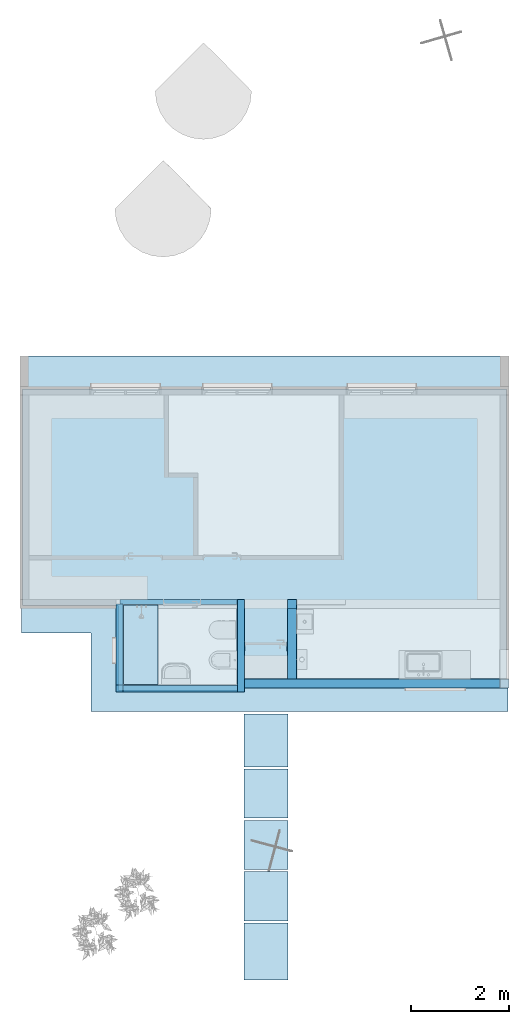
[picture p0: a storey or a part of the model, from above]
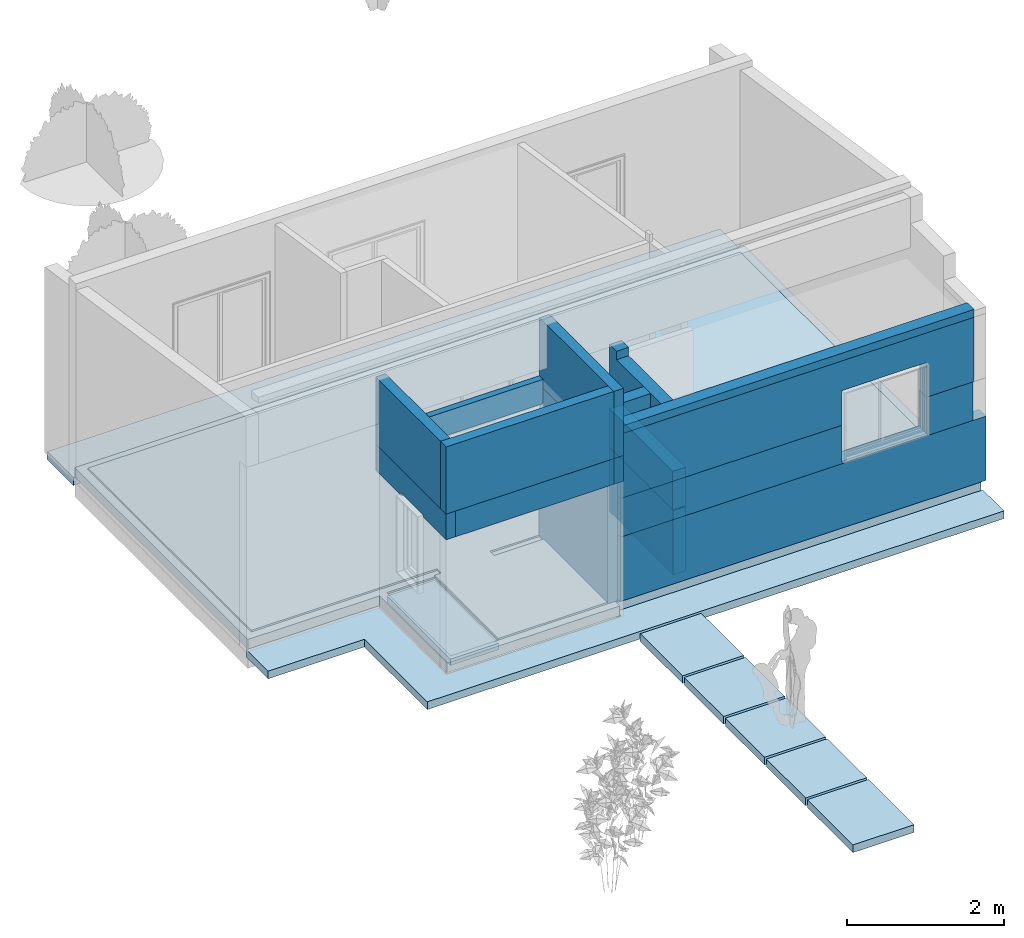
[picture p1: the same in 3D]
Properties of the parts of a building model (IFC2X3)

# File
Description: ViewDefinition [CoordinationView_V2.0]
File name: Project Number
Time: 2021-10-06T08:26:32
Written by: The EXPRESS Data Manager Version 5.02.0100.07 : 28 Aug 2013
Made in: 20200210_1400(x64) - Exporter 20.2.12.1 - Alternate UI 20.2.12.1
Comment: STEP Physical File produced by: The EXPRESS Data Manager Version 5.02.0100.07 : 28 Aug 2013 * Module: EDMstepFileFactory/EDMstandAlone * Creation date: Wed Oct 06 08:26:32 2021 * Host: d-417 * Database: C:\Users\msoler\AppData\Local\Temp\011061c9-1817-4c47-bff8-884cf63e469e\37fb6d74-e1f5-403b-9660-fe2e54388b5f\ifc * Database version: 5507 * Database creation date: Wed Oct 06 08:26:29 2021 * Schema: IFC2X3 * Model: DataRepository.ifc * Model creation date: Wed Oct 06 08:26:30 2021 * Header model: DataRepository.ifc_HeaderModel * Header model creation date: Wed Oct 06 08:26:30 2021 * EDMuser: sdai-user * EDMgroup: sdai-group * License ID and type: 5605 : Permanent license. Expiry date: * EDMstepFileFactory options: 020000

# IfcProject, Project Number
LongName: Project Name; Phase: Project Status

# IfcSite, Surface:604594
RefLatitude: 42, 21, 31, 181945; RefLongitude: -71, -3, -24, -263305; RefElevation: 0 m
Pset_ProductRequirements - Category: Topography

# IfcBuilding
Pset_BuildingCommon - NumberOfStoreys: 2
Pset_ProductRequirements - Category: Project Information

# IfcBuildingStorey: Level:8mm Head (2)
Pset_ProductRequirements - Category: Levels
Name | LongName = Pset_AirSideSystemInformation, Name = Pset_ProductRequirements, Name | Elevation (m)
Nivel 0.0 | Nivel 0.0 | 0
Nivel 1 | Nivel 1 | 2.7

# IfcSpace (6)
In: Nivel 0.0
InteriorOrExteriorSpace: INTERNAL
Pset_ProductRequirements - Category: Rooms
Pset_SpaceCommon - Category: Rooms; FloorCovering: Cerámico; CeilingCovering: placa yeso suspendido
Name | LongName = Pset_AirSideSystemInformation, Name = Pset_ProductRequirements, Name | Reference
1 | Hall distribuidor y paso | Hall distribuidor y paso 1
2 | Estar comedor | Estar comedor 2
4 | Dormitorio 1 | Dormitorio 1 4
5 | Dormitorio 2 | Dormitorio 2 5
6 | Baño | Baño 6 | Pset_SpaceCommon - WallCovering: cerámico
3 | Lavadero | Lavadero 3 | Pset_SpaceCommon - WallCovering: cerámico

# IfcBuildingElementProxy: Barberry - 1.0 Meters (3)
In: Nivel 0.0
Type - Pset_BuildingElementProxyCommon - Reference: Barberry - 1.0 Meters
Type - Pset_ProductRequirements - Category: Planting
Type - Pset_QuantityTakeOff - Reference: Barberry - 1.0 Meters
Pset_BuildingElementProxyCommon - sets with these values: 2
Name (M_RPC Shrub:Barberry - 1.0 Meters:...)
617424
617426
707226

# IfcBuildingElementProxy: Enscape AssetDefinition - Bamboo 5 (2)
In: Nivel 0.0
Type - Pset_BuildingElementProxyCommon - Reference: Enscape AssetDefinition - Bamboo 5
Type - Pset_ProductRequirements - Category: Planting
Type - Pset_QuantityTakeOff - Reference: Enscape AssetDefinition - Bamboo 5
Pset_BuildingElementProxyCommon - sets with these values: 2
Name (Bamboo:Enscape AssetDefinition - Bamboo 5:...)
669530
671551

# IfcBuildingElementProxy: People_01_Multiple_views_persona_01_Vistas_multiples_3530 (2)
In: Nivel 0.0
Type - Material: Sombra escala
Type - Pset_BuildingElementProxyCommon - Reference: People_01_Multiple_views_persona_01_Vistas_multiples_3530
Type - Pset_ProductRequirements - Category: Entourage
Type - Pset_QuantityTakeOff - Reference: People_01_Multiple_views_persona_01_Vistas_multiples_3530
Pset_BuildingElementProxyCommon - sets with these values: 2
Name (People_01_Multiple_views_persona_01_Vistas_multiples_3530:People_01_Multiple_views_persona_01_Vistas_multiples_3530:...)
621565
707233

# IfcBuildingElementProxy: Slab Edge:Slab Edge, Slab Edge:Slab Edge:727210
In: Nivel 0.0
Pset_BuildingElementProxyCommon - Reference: Slab Edge; sets with these values: 2
Pset_ProductRequirements - Category: Slab Edges

# IfcBuildingElementProxy: calentador solar techo inclinado, calentador solar techo inclinado:calentador solar techo inclinado:707159
In: Nivel 1
Type - Material: Aluminio, Acero inoxidable, UHMW, rojo, Laminado, marino
Type - Pset_BuildingElementProxyCommon - Reference: calentador solar techo inclinado
Type - Pset_ManufacturerTypeInformation - Manufacturer: Bicentenario Calentadores solares
Type - Pset_ProductRequirements - Category: Mechanical Equipment
Type - Pset_QuantityTakeOff - Reference: calentador solar techo inclinado
Pset_BuildingElementProxyCommon - sets with these values: 2

# IfcCovering: Compound Ceiling:1282-Aplicado de yeso (4)
Type - PredefinedType: CEILING
Type - Pset_CoveringCommon - Reference: 1282-Aplicado de yeso; TotalThickness: 0.02 m
Type - Pset_ElementShading - Roughness: 0.3048 m
Type - Pset_ProductRequirements - Category: Ceilings
Type - Pset_QuantityTakeOff - Reference: 1282-Aplicado de yeso
Material: Cielorraso aplicado de yeso 0.02 m
Name (Compound Ceiling:1282-Aplicado de yeso:...) | In
452097 | Nivel 1
452149 | Nivel 0.0
707047 | 6
721033 | Nivel 0.0

# IfcDistributionPort (8)
Description: Flow
Name | FlowDirection
Port_707095 | SINK
Port_707095 | SOURCE
Port_707096 | SINK
2 x Port_707096 | SOURCE
Port_707125 | SINK
2 x Port_707159 | SOURCEANDSINK

# IfcDoor: P1, Puerta acceso:P1:725328
In: Nivel 0.0
Type - OperationType: SINGLE_SWING_RIGHT; ParameterTakesPrecedence: no; Sizeable: no; Material: Aluminum, Metal, Paint Finish, White, Matte
Type - Puerta acceso:P1:725328 - PanelOperation: SWINGING
OverallHeight: 2.1 m; OverallWidth: 0.85 m
Pset_DoorCommon - IsExternal: no; Reference: P1
Pset_ProductRequirements - Category: Doors
Pset_QuantityTakeOff - Reference: P1

# IfcDoor: P3 (3)
In: Nivel 0.0
Type - ParameterTakesPrecedence: no; Sizeable: no; Material: Bronce Platil, 0 - BLANCO, Pintura Esmalte Blanco Satinado
OverallHeight: 2.1 m; OverallWidth: 0.78 m
Pset_DoorCommon - IsExternal: no; Reference: P3
Pset_ProductRequirements - Category: Doors
Pset_QuantityTakeOff - Reference: P3
Name (Puerta Interior:P3:...)
707092
707093
707094

# IfcFlowTerminal: Bacha-Ferrum-Qubiq-L12K:Sin Agujero, Bacha-Ferrum-Qubiq-L12K:Sin Agujero:707125
In: 3
Material: Ceramica - Ferrum - Blanco
Pset_DistributionFlowElementCommon - Reference: Sin Agujero; sets with these values: 2
Pset_ManufacturerTypeInformation - Manufacturer: Ferrum
Pset_ProductRequirements - Category: Plumbing Fixtures

# IfcFlowTerminal: Bidet-Ferrum-Veneto-1_y_3_Agujeros:1 Agujero, Bidet-Ferrum-Veneto-1_y_3_Agujeros:1 Agujero:707096
In: 6
Material: Ceramica - Ferrum - Blanco
Pset_DistributionFlowElementCommon - Reference: 1 Agujero; sets with these values: 2
Pset_ManufacturerTypeInformation - Manufacturer: Ferrum
Pset_ProductRequirements - Category: Plumbing Fixtures

# IfcFlowTerminal: Cdo Ducha:Cdo Ducha, Cdo Ducha:Cdo Ducha:707099
In: 6
Material: 0 - BLANCO, Metal - Cromo pulido
Pset_DistributionFlowElementCommon - Reference: Cdo Ducha; sets with these values: 2
Pset_ProductRequirements - Category: Plumbing Fixtures

# IfcFlowTerminal: Inodoro-Ferrum-Veneto-Corto:Inodoro Corto, Inodoro-Ferrum-Veneto-Corto:Inodoro Corto:707095
In: 6
Material: Ceramica - Ferrum - Blanco
Pset_DistributionFlowElementCommon - Reference: Inodoro Corto; sets with these values: 2
Pset_ManufacturerTypeInformation - Manufacturer: Ferrum
Pset_ProductRequirements - Category: Plumbing Fixtures

# IfcFlowTerminal: Inodoro-Ferrum-Veneto-Tapa_y_Asiento:Tapa de Inodoro, Inodoro-Ferrum-Veneto-Tapa_y_Asiento:Tapa de Inodoro:707270
In: 6
Material: Plastico - Ferrum - Urea - Blanco
Pset_DistributionFlowElementCommon - Reference: Tapa de Inodoro; sets with these values: 2
Pset_ManufacturerTypeInformation - Manufacturer: Ferrum
Pset_ProductRequirements - Category: Plumbing Fixtures

# IfcFlowTerminal: Lavatorio:Lavatorio, Lavatorio:Lavatorio:707098
In: 6
Material: Porcelain
Pset_DistributionFlowElementCommon - Reference: Lavatorio; sets with these values: 2
Pset_ProductRequirements - Category: Plumbing Fixtures

# IfcFlowTerminal: M_Sink Kitchen-Single:760 x 535mm, M_Sink Kitchen-Single:760 x 535mm:707124
In: 2
Material: Steel, Polished
Pset_DistributionFlowElementCommon - Reference: 760 x 535mm; sets with these values: 2
Pset_ProductRequirements - Category: Plumbing Fixtures

# IfcFurnishingElement: EH-Esquentador a Gáz, CALEFON:EH-Esquentador a Gáz:707126
In: 3
Type - Material: Glass, EH - Preto, EH - Branco
Pset_ManufacturerTypeInformation - Manufacturer: Vulcano
Pset_ProductRequirements - Category: Casework
Pset_QuantityTakeOff - Reference: EH-Esquentador a Gáz

# IfcFurnishingElement: Mesada 1.45m, M_Counter Top w Sink:Mesada 1.45m:707123
In: 2
Type - Material: Stone
Pset_ProductRequirements - Category: Casework
Pset_QuantityTakeOff - Reference: Mesada 1.45m

# IfcOpeningElement: Opening (21)
Name | In
Basic Wall:Pe-SF-002:706994:1 | Nivel 0.0 | Pset_ElementShading - Roughness: 0.3048 m; Pset_ProductRequirements - Category: Walls; Pset_QuantityTakeOff - Reference: Pe-SF-002; sets with these values: 2
Basic Wall:Pi-SF-050:706999 | Nivel 0.0 | Pset_ElementShading - Roughness: 0.3048 m; Pset_ProductRequirements - Category: Walls; Pset_QuantityTakeOff - Reference: Pi-SF-050; sets with these values: 2
Floor:Platea de fundación:707003:2 | Nivel 0.0 | Pset_ElementShading - Roughness: 0.9144 m; Pset_ProductRequirements - Category: Floors; Pset_OpeningElementCommon - Reference: Platea de fundación; sets with these values: 2
Basic Wall:Pe-SF-001:707091:1 | Nivel 0.0 | Pset_ElementShading - Roughness: 0.3048 m; Pset_ProductRequirements - Category: Walls; Pset_QuantityTakeOff - Reference: Pe-SF-001; sets with these values: 2
Ventana1,20x1.20:V1:817578:1 | Nivel 0.0
M_Counter Top w Sink:Mesada 1.45m:707123:1 | 2 | Pset_ProductRequirements - Category: Casework; Pset_OpeningElementCommon - Reference: Mesada 1.45m; sets with these values: 2
Ventana batiente horizontal V2:V2:805811:1 | Nivel 0.0
2 x Basic Wall:Pe-SF-005:808462 | Nivel 0.0 | Pset_ElementShading - Roughness: 0.3048 m; Pset_ProductRequirements - Category: Walls; Pset_QuantityTakeOff - Reference: Pe-SF-005; sets with these values: 2
2 x Basic Wall:Pe-SF-002:816235 | Nivel 0.0 | Pset_ElementShading - Roughness: 0.3048 m; Pset_ProductRequirements - Category: Walls; Pset_QuantityTakeOff - Reference: Pe-SF-002; sets with these values: 2
Vtana Corrediza:PV1:707120:1 | Nivel 0.0
Premarco metálico:Premarco metálico PV1:707163:1 | Nivel 0.0
Vtana Corrediza:PV1:707121:1 | Nivel 0.0
Premarco metálico:Premarco metálico PV1:707164:1 | Nivel 0.0
Vtana Corrediza:PV1:707122:1 | Nivel 0.0
Premarco metálico:Premarco metálico PV1:707165:1 | Nivel 0.0
Puerta Interior:P3:707092:1 | Nivel 0.0
Puerta Interior:P3:707093:1 | Nivel 0.0
Puerta Interior:P3:707094:1 | Nivel 0.0
Puerta acceso:P1:725328:1 | Nivel 0.0

# IfcRoof: Basic Roof:PC-SF-100, Basic Roof:PC-SF-100:707031
In: Nivel 1
Pset_ElementShading - Roughness: 0.9144 m
Pset_ProductRequirements - Category: Roofs
Pset_QuantityTakeOff - Reference: PC-SF-100
Pset_RoofCommon - IsExternal: yes; Reference: PC-SF-100; ProjectedArea: 51.6627 m2; TotalArea: 52.2406 m2

# IfcRoof: Basic Roof:PC-SF-101 (2)
In: Nivel 1
Pset_ElementShading - Roughness: 0.9144 m
Pset_ProductRequirements - Category: Roofs
Pset_QuantityTakeOff - Reference: PC-SF-101
Pset_RoofCommon - IsExternal: yes; Reference: PC-SF-101
Name (Basic Roof:PC-SF-101:...) | ProjectedArea (m2) = TotalArea (m2)
726101 | 3.61079
726763 | 7.49576

# IfcSlab: Basic Roof:PC-SF-100, Basic Roof:PC-SF-100:707031
In: Nivel 1
PredefinedType: ROOF; Material: Chapa sinuzoidal 0.004 m, Perfileria PGC s/cálculo+ Material Aislante 0.15 m
Pset_ElementShading - Roughness: 0.9144 m
Pset_ProductRequirements - Category: Roofs
Pset_QuantityTakeOff - Reference: PC-SF-100
Pset_ReinforcementBarPitchOfSlab - Description: Cubierta inclinada-Perfileria PGC s/cálculo+Aislación térmica+chapa; Reference: PC-SF-100
Pset_SlabCommon - IsExternal: yes; Reference: PC-SF-100; ThermalTransmittance: 13250 kg/K/s3; PitchAngle: 8.59437 deg

# IfcSlab: Basic Roof:PC-SF-101 (2)
In: Nivel 1
PredefinedType: ROOF; Material: Membrana Geotextil 0.005 m, Mortero de pendiente 0.05 m, Poliestireno expandido 0.03 m, Membrana asfáltica 0.003 m, OSB 0.012 m, Perfileria PGC s/cálculo+ Material Aislante 0.15 m
Pset_ElementShading - Roughness: 0.9144 m
Pset_ProductRequirements - Category: Roofs
Pset_QuantityTakeOff - Reference: PC-SF-101
Pset_ReinforcementBarPitchOfSlab - Description: Cubierta plana- Perfilería PGC s/c+OSB+Ailación térmica e hidrófuga; Reference: PC-SF-101
Pset_SlabCommon - PitchAngle: 0 deg; IsExternal: yes; Reference: PC-SF-101; ThermalTransmittance: 0.988239 kg/K/s3
Name (Basic Roof:PC-SF-101:...)
726101
726763

# IfcSlab: Floor:Piso Cerámico (2)
In: Nivel 0.0
Type - PredefinedType: FLOOR; Material: Ceramic Tile 0.01 m, Concrete, Sand/Cement Screed 0.015 m
Type - Pset_ElementShading - Roughness: 0.9144 m
Type - Pset_ProductRequirements - Category: Floors
Type - Pset_QuantityTakeOff - Reference: Piso Cerámico
Type - Pset_ReinforcementBarPitchOfSlab - Description: Receptáculo baño; Reference: Piso Cerámico
Type - Pset_SlabCommon - IsExternal: no; Reference: Piso Cerámico; ThermalTransmittance: 44.104 kg/K/s3
Pset_SlabCommon - LoadBearing: no; PitchAngle: 0 deg
Name (Floor:Piso Cerámico:...)
707053
707115

# IfcSlab: Floor:Platea de fundación, Floor:Platea de fundación:707003
In: Nivel 0.0
Type - PredefinedType: FLOOR; Material: Concrete, Cast In Situ 0.15 m
Type - Pset_ElementShading - Roughness: 0.9144 m
Type - Pset_ProductRequirements - Category: Floors
Type - Pset_QuantityTakeOff - Reference: Platea de fundación
Type - Pset_ReinforcementBarPitchOfSlab - Description: Platea de fundación; Reference: Platea de fundación
Type - Pset_SlabCommon - IsExternal: no; Reference: Platea de fundación; ThermalTransmittance: 6.97333 kg/K/s3
Pset_SlabCommon - LoadBearing: no; PitchAngle: 0 deg

# IfcSlab: Floor:Platea de fundación, receptaculo baño, Floor:Platea de fundación, receptaculo baño:707108
In: Nivel 0.0
Type - PredefinedType: FLOOR; Material: Concrete, Cast In Situ 0.1 m
Type - Pset_ElementShading - Roughness: 0.9144 m
Type - Pset_ProductRequirements - Category: Floors
Type - Pset_QuantityTakeOff - Reference: Platea de fundación, receptaculo baño
Type - Pset_ReinforcementBarPitchOfSlab - Description: Receptáculo baño; Reference: Platea de fundación, receptaculo baño
Type - Pset_SlabCommon - IsExternal: no; Reference: Platea de fundación, receptaculo baño; ThermalTransmittance: 10.46 kg/K/s3
Pset_SlabCommon - LoadBearing: no; PitchAngle: 0 deg

# IfcSlab: Floor:Vereda de acceso, Floor:Vereda de acceso:705603:5
In: Nivel 0.0
Type - PredefinedType: FLOOR; Material: Hormigón Armado veredines 0.12 m
Type - Pset_ElementShading - Roughness: 0.9144 m
Type - Pset_ProductRequirements - Category: Floors
Type - Pset_QuantityTakeOff - Reference: Vereda de acceso
Type - Pset_ReinforcementBarPitchOfSlab - Description: Vereda de acceso; Reference: Vereda de acceso
Type - Pset_SlabCommon - Reference: Vereda de acceso; IsExternal: no; ThermalTransmittance: 8.71667 kg/K/s3
Pset_SlabCommon - LoadBearing: no; PitchAngle: 0 deg

# IfcSlab: Floor:Vereda de acceso (4)
In: Nivel 0.0
Type - PredefinedType: FLOOR
Type - Pset_ElementShading - Roughness: 0.9144 m
Type - Pset_ProductRequirements - Category: Floors
Type - Pset_QuantityTakeOff - Reference: Vereda de acceso
Type - Pset_ReinforcementBarPitchOfSlab - Description: Vereda de acceso; Reference: Vereda de acceso
Type - Pset_SlabCommon - Reference: Vereda de acceso; IsExternal: no; ThermalTransmittance: 8.71667 kg/K/s3
Material: Hormigón Armado veredines 0.12 m
Pset_SlabCommon - LoadBearing: no; PitchAngle: 0 deg
Name (Floor:Vereda de acceso:...)
705603
705603:2
705603:3
705603:4

# IfcSlab: Floor:Veredín perimetral, Floor:Veredín perimetral:707015:2
In: Nivel 0.0
Type - PredefinedType: FLOOR; Material: Hormigón Armado veredines 0.12 m
Type - Pset_ElementShading - Roughness: 0.9144 m
Type - Pset_ProductRequirements - Category: Floors
Type - Pset_QuantityTakeOff - Reference: Veredín perimetral
Type - Pset_ReinforcementBarPitchOfSlab - Description: Veredín perimetral; Reference: Veredín perimetral
Type - Pset_SlabCommon - IsExternal: no; Reference: Veredín perimetral; ThermalTransmittance: 8.71667 kg/K/s3
Pset_SlabCommon - LoadBearing: no; PitchAngle: 0 deg

# IfcSlab: Floor:Veredín perimetral, Floor:Veredín perimetral:707015
In: Nivel 0.0
Type - PredefinedType: FLOOR
Type - Pset_ElementShading - Roughness: 0.9144 m
Type - Pset_ProductRequirements - Category: Floors
Type - Pset_QuantityTakeOff - Reference: Veredín perimetral
Type - Pset_ReinforcementBarPitchOfSlab - Description: Veredín perimetral; Reference: Veredín perimetral
Type - Pset_SlabCommon - IsExternal: no; Reference: Veredín perimetral; ThermalTransmittance: 8.71667 kg/K/s3
Material: Hormigón Armado veredines 0.12 m
Pset_SlabCommon - LoadBearing: no; PitchAngle: 0 deg

# IfcWall: Basic Wall:Pe-SF-002, Basic Wall:Pe-SF-002:706986
In: Nivel 0.0
Type - PredefinedType: STANDARD; Material: EIFS 0.05 m, Aislación hidrófuga 0.005 m, OSB 0.011 m, Bastidor metálico 0.1 m, Placa roca de Yeso 12,5mm 0.012 m
Type - Pset_ElementShading - Roughness: 0.3048 m
Type - Pset_ProductRequirements - Category: Walls
Type - Pset_QuantityTakeOff - Reference: Pe-SF-002
Type - Pset_ReinforcementBarPitchOfWall - Description: Pe-EIFS+SIP+p.yeso; Reference: Pe-SF-002
Type - Pset_WallCommon - IsExternal: no; Reference: Pe-SF-002; ThermalTransmittance: 0.158843 kg/K/s3
Material: EIFS, Aislación hidrófuga, OSB, Bastidor metálico, Placa roca de Yeso 12,5mm
Pset_WallCommon - LoadBearing: no; IsExternal: yes; ExtendToStructure: no

# IfcWall: Basic Wall:Pe-SF-006 (2)
In: Nivel 0.0
Type - PredefinedType: STANDARD; Material: Revestimiento exterior tipo siding 0.012 m, Aislación hidrófuga 0.005 m, OSB 0.011 m, Bastidor metálico+Aislación térmica 0.1 m, Placa roca de Yeso 12,5mm 0.012 m, Revestimiento Cerámico muro 0.012 m
Type - Pset_ElementShading - Roughness: 0.3048 m
Type - Pset_ProductRequirements - Category: Walls
Type - Pset_QuantityTakeOff - Reference: Pe-SF-006
Type - Pset_ReinforcementBarPitchOfWall - Description: Pe-revest. exterior+SF+p.yeso+rev.cerámico; Reference: Pe-SF-006
Type - Pset_WallCommon - IsExternal: no; Reference: Pe-SF-006; ThermalTransmittance: 0.236317 kg/K/s3
Pset_WallCommon - LoadBearing: no; IsExternal: yes; ExtendToStructure: no
Name (Basic Wall:Pe-SF-006:...)
707314 | Material: Revestimiento exterior tipo siding, Aislación hidrófuga, OSB, Bastidor metálico+Aislación térmica, Placa roca de Yeso 12,5mm, Revestimiento Cerámico muro
807294

# IfcWall: Basic Wall:Pi-SF-051, Basic Wall:Pi-SF-051:709278
In: Nivel 0.0
Type - PredefinedType: STANDARD; Material: Placa roca de Yeso 12,5mm 0.0125 m, Bastidor metálico 0.07 m, Placa roca de Yeso 12,5mm 0.0125 m, Revestimiento Cerámico muro 0.0125 m
Type - Pset_ElementShading - Roughness: 0.3048 m
Type - Pset_ProductRequirements - Category: Walls
Type - Pset_QuantityTakeOff - Reference: Pi-SF-051
Type - Pset_ReinforcementBarPitchOfWall - Description: Pi- p.yeso+SF+ p.yeso+rev.cerámico; Reference: Pi-SF-051
Type - Pset_WallCommon - IsExternal: no; Reference: Pi-SF-051; ThermalTransmittance: 0.355819 kg/K/s3
Material: Placa roca de Yeso 12,5mm (2), Bastidor metálico, Revestimiento Cerámico muro
Pset_WallCommon - LoadBearing: no; ExtendToStructure: no

# IfcWallStandardCase: Basic Wall:Pe-SF-001 (5)
In: Nivel 0.0
Type - PredefinedType: STANDARD; Material: EIFS 0.05 m, Aislación hidrófuga 0.005 m, OSB 0.011 m, Bastidor metálico 0.1 m, Placa cementicia 0.012 m
Type - Pset_ElementShading - Roughness: 0.3048 m
Type - Pset_ProductRequirements - Category: Walls
Type - Pset_QuantityTakeOff - Reference: Pe-SF-001
Type - Pset_ReinforcementBarPitchOfWall - Description: Pe-EIFS+SF+p.cem; Reference: Pe-SF-001
Type - Pset_WallCommon - IsExternal: no; Reference: Pe-SF-001; ThermalTransmittance: 0.158554 kg/K/s3
Pset_WallCommon - LoadBearing: no; IsExternal: yes
Name (Basic Wall:Pe-SF-001:...) | ExtendToStructure
706985 | yes
707091 | no
708804 | no
724327 | no
818624 | no

# IfcWallStandardCase: Basic Wall:Pe-SF-002 (10)
In: Nivel 0.0
Type - PredefinedType: STANDARD; Material: EIFS 0.05 m, Aislación hidrófuga 0.005 m, OSB 0.011 m, Bastidor metálico 0.1 m, Placa roca de Yeso 12,5mm 0.012 m
Type - Pset_ElementShading - Roughness: 0.3048 m
Type - Pset_ProductRequirements - Category: Walls
Type - Pset_QuantityTakeOff - Reference: Pe-SF-002
Type - Pset_ReinforcementBarPitchOfWall - Description: Pe-EIFS+SIP+p.yeso; Reference: Pe-SF-002
Type - Pset_WallCommon - IsExternal: no; Reference: Pe-SF-002; ThermalTransmittance: 0.158843 kg/K/s3
Pset_WallCommon - LoadBearing: no; IsExternal: yes
Name (Basic Wall:Pe-SF-002:...) | ExtendToStructure
706994 | no
707189 | yes
708803 | no
725217 | yes
799828 | yes
808198 | no
815958 | yes
816024 | no
816235 | no
816279 | yes

# IfcWallStandardCase: Basic Wall:Pe-SF-003 (3)
In: Nivel 0.0
Type - PredefinedType: STANDARD; Material: EIFS 0.05 m, Aislación hidrófuga 0.005 m, OSB 0.011 m, Bastidor metálico 0.1 m, Placa roca de Yeso 12,5mm 0.012 m, Revestimiento Cerámico muro 0.012 m
Type - Pset_ElementShading - Roughness: 0.3048 m
Type - Pset_ProductRequirements - Category: Walls
Type - Pset_QuantityTakeOff - Reference: Pe-SF-003
Type - Pset_ReinforcementBarPitchOfWall - Description: Pe-EIFS+SF+p.yeso+rev. cerámico; Reference: Pe-SF-003
Type - Pset_WallCommon - IsExternal: no; Reference: Pe-SF-003; ThermalTransmittance: 0.158591 kg/K/s3
Pset_WallCommon - LoadBearing: no; IsExternal: yes
Name (Basic Wall:Pe-SF-003:...) | ExtendToStructure
708802 | no
815957 | yes
816023 | no

# IfcWallStandardCase: Basic Wall:Pe-SF-004 (3)
In: Nivel 0.0
Type - PredefinedType: STANDARD; Material: Revestimiento exterior tipo siding 0.012 m, Aislación hidrófuga 0.005 m, OSB 0.011 m, Bastidor metálico+Aislación térmica 0.1 m, Aislación hidrófuga 0.005 m, Placa cementicia 0.012 m
Type - Pset_ElementShading - Roughness: 0.3048 m
Type - Pset_ProductRequirements - Category: Walls
Type - Pset_QuantityTakeOff - Reference: Pe-SF-004
Type - Pset_ReinforcementBarPitchOfWall - Description: Pe-revest. exterior+SF+p.cem; Reference: Pe-SF-004
Type - Pset_WallCommon - IsExternal: no; Reference: Pe-SF-004; ThermalTransmittance: 0.234576 kg/K/s3
Pset_WallCommon - LoadBearing: no; IsExternal: yes; ExtendToStructure: no
Name (Basic Wall:Pe-SF-004:...)
707316
708433
807296

# IfcWallStandardCase: Basic Wall:Pe-SF-005 (3)
In: Nivel 0.0
Type - PredefinedType: STANDARD; Material: Revestimiento exterior tipo siding 0.012 m, Aislación hidrófuga 0.005 m, OSB 0.011 m, Bastidor metálico+Aislación térmica 0.1 m, Placa roca de Yeso 12,5mm 0.012 m
Type - Pset_ElementShading - Roughness: 0.3048 m
Type - Pset_ProductRequirements - Category: Walls
Type - Pset_QuantityTakeOff - Reference: Pe-SF-005
Type - Pset_ReinforcementBarPitchOfWall - Description: Pe-revest. exterior+SF+p.yeso; Reference: Pe-SF-005
Type - Pset_WallCommon - IsExternal: no; Reference: Pe-SF-005; ThermalTransmittance: 0.236877 kg/K/s3
Pset_WallCommon - LoadBearing: no; IsExternal: yes; ExtendToStructure: no
Name (Basic Wall:Pe-SF-005:...)
808462
808463
808679

# IfcWallStandardCase: Basic Wall:Pe-SF-006, Basic Wall:Pe-SF-006:708431
In: Nivel 0.0
Type - PredefinedType: STANDARD; Material: Revestimiento exterior tipo siding 0.012 m, Aislación hidrófuga 0.005 m, OSB 0.011 m, Bastidor metálico+Aislación térmica 0.1 m, Placa roca de Yeso 12,5mm 0.012 m, Revestimiento Cerámico muro 0.012 m
Type - Pset_ElementShading - Roughness: 0.3048 m
Type - Pset_ProductRequirements - Category: Walls
Type - Pset_QuantityTakeOff - Reference: Pe-SF-006
Type - Pset_ReinforcementBarPitchOfWall - Description: Pe-revest. exterior+SF+p.yeso+rev.cerámico; Reference: Pe-SF-006
Type - Pset_WallCommon - IsExternal: no; Reference: Pe-SF-006; ThermalTransmittance: 0.236317 kg/K/s3
Pset_WallCommon - LoadBearing: no; IsExternal: yes; ExtendToStructure: no

# IfcWallStandardCase: Basic Wall:Pi-SF-050 (8)
In: Nivel 0.0
Type - PredefinedType: STANDARD; Material: Placa roca de Yeso 12,5mm 0.0125 m, Bastidor metálico 0.07 m, Placa roca de Yeso 12,5mm 0.0125 m
Type - Pset_ElementShading - Roughness: 0.3048 m
Type - Pset_ProductRequirements - Category: Walls
Type - Pset_QuantityTakeOff - Reference: Pi-SF-050
Type - Pset_ReinforcementBarPitchOfWall - Description: Pi- p.yeso+SF+ p.yeso; Reference: Pi-SF-050
Type - Pset_WallCommon - IsExternal: no; Reference: Pi-SF-050; ThermalTransmittance: 0.357143 kg/K/s3
Pset_WallCommon - LoadBearing: no
Name (Basic Wall:Pi-SF-050:...) | ExtendToStructure
706995 | yes
706996 | yes
706997 | yes
706998 | yes
706999 | yes
799671 | no
808714 | no
808716 | no

# IfcWallStandardCase: Basic Wall:Pi-SF-051, Basic Wall:Pi-SF-051:808715
In: Nivel 0.0
Type - PredefinedType: STANDARD; Material: Placa roca de Yeso 12,5mm 0.0125 m, Bastidor metálico 0.07 m, Placa roca de Yeso 12,5mm 0.0125 m, Revestimiento Cerámico muro 0.0125 m
Type - Pset_ElementShading - Roughness: 0.3048 m
Type - Pset_ProductRequirements - Category: Walls
Type - Pset_QuantityTakeOff - Reference: Pi-SF-051
Type - Pset_ReinforcementBarPitchOfWall - Description: Pi- p.yeso+SF+ p.yeso+rev.cerámico; Reference: Pi-SF-051
Type - Pset_WallCommon - IsExternal: no; Reference: Pi-SF-051; ThermalTransmittance: 0.355819 kg/K/s3
Pset_WallCommon - LoadBearing: no; ExtendToStructure: no

# IfcWindow: PV1 (3)
In: Nivel 0.0
Type - ParameterTakesPrecedence: no; Sizeable: no; Material: Glass, Laminate, White
OverallHeight: 2.1 m; OverallWidth: 1.4 m
Pset_ProductRequirements - Category: Windows
Pset_QuantityTakeOff - Reference: PV1
Pset_WindowCommon - IsExternal: yes; Reference: PV1
Name (Vtana Corrediza:PV1:...)
707120
707121
707122

# IfcWindow: Premarco metálico PV1 (3)
In: Nivel 0.0
Type - ParameterTakesPrecedence: no; Sizeable: no; Material: Chapa plegada
OverallHeight: 2.13 m; OverallWidth: 1.44 m
Pset_ProductRequirements - Category: Windows
Pset_QuantityTakeOff - Reference: Premarco metálico PV1
Pset_WindowCommon - IsExternal: yes; Reference: Premarco metálico PV1
Name (Premarco metálico:Premarco metálico PV1:...)
707163
707164
707165

# IfcWindow: V1, Ventana1,20x1.20:V1:817578
In: Nivel 0.0
Type - ConstructionType: OTHER_CONSTRUCTION; OperationType: DOUBLE_PANEL_VERTICAL; ParameterTakesPrecedence: no; Sizeable: no; Classification: B2020100 Windows (Uniformat); Material: Chapa plegada, NBS_Concept, NBS_Glass_Double
OverallHeight: 1.1 m; OverallWidth: 1.25 m
Pset_DoorWindowGlazingType - GlassLayers: 0; FillGas: n/a; GlassColor: n/a; IsTempered: no; IsLaminated: no; IsCoated: no; IsWired: no; Translucency: 0; Reflectivity: 0; BeamRadiationTransmittance: 0; SolarHeatGainTransmittance: 0; ThermalTransmittanceSummer: 0 kg/K/s3; ThermalTransmittanceWinter: 0 kg/K/s3
Pset_ElementShading - Color: n/a
Pset_ManufacturerOccurrence - BarCode: n/a; SerialNumber: n/a
Pset_ManufacturerTypeInformation - ModelReference: Double window with side hung opening lights; Manufacturer: n/a
Pset_ProductRequirements - Name: ExternalWindowSystem_Double_SideHungLight-SideHungLight; Category: Windows
Pset_QuantityTakeOff - Reference: n/a
Pset_WindowCommon - IsExternal: no; Reference: n/a; FireRating: n/a; AcousticRating: n/a; SecurityRating: n/a; Infiltration: 0 m3/s; ThermalTransmittance: 0 kg/K/s3; GlazingAreaFraction: 0; SmokeStop: no

# IfcWindow: V2, Ventana batiente horizontal V2:V2:805811
In: Nivel 0.0
Type - ParameterTakesPrecedence: no; Sizeable: no; Material: Chapa plegada, Glass, Aluminum
OverallHeight: 1.2 m; OverallWidth: 0.55 m
Pset_ProductRequirements - Category: Windows
Pset_QuantityTakeOff - Reference: V2
Pset_WindowCommon - IsExternal: yes; Reference: V2
